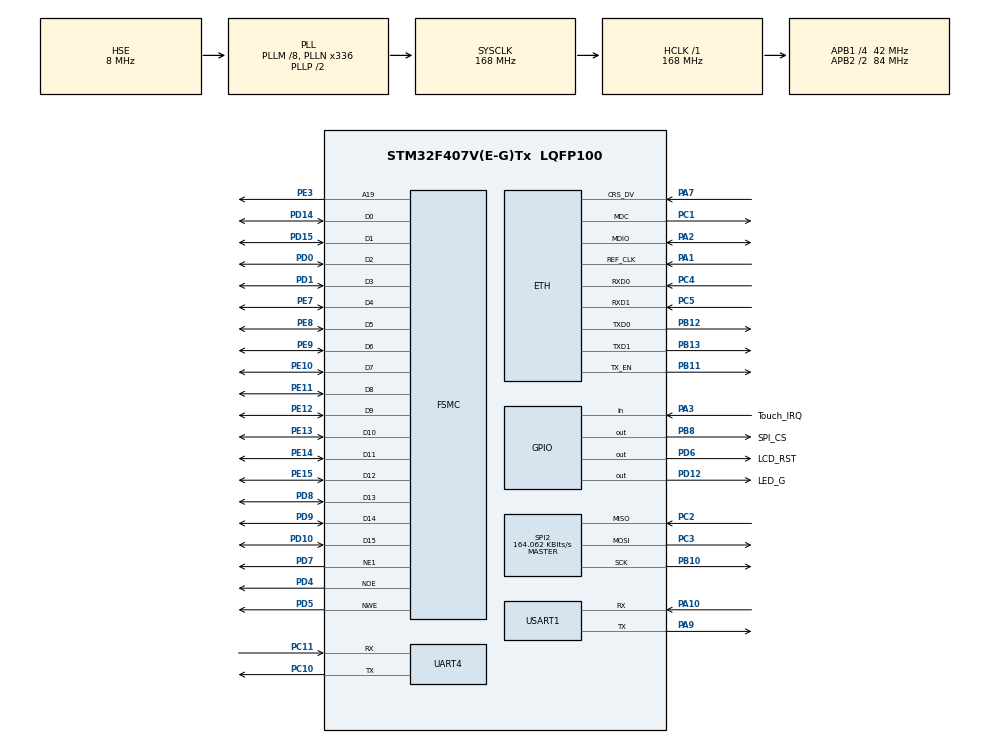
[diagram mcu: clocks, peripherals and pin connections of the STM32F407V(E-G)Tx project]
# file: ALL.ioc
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ETH.MediaInterface=ETH_MEDIA_INTERFACE_RMII
LWIP.GATEWAY_ADDRESS=192.168.000.102
LWIP.IP_ADDRESS=192.168.000.103
LWIP.LWIP_DHCP=0
LWIP.NETMASK_ADDRESS=255.255.255.000
LWIP.Version=v1.5.0_RC0_20160211_Cube
Mcu.Family=STM32F4
Mcu.Name=STM32F407V(E-G)Tx
Mcu.Package=LQFP100
NVIC.PriorityGroup=NVIC_PRIORITYGROUP_4
PA1.Mode=RMII
PA1.Signal=ETH_REF_CLK
PA10.Mode=Asynchronous
PA10.Signal=USART1_RX
PA13.Mode=JTAG_5_pins
PA13.Signal=SYS_JTMS-SWDIO
PA14.Mode=JTAG_5_pins
PA14.Signal=SYS_JTCK-SWCLK
PA15.Mode=JTAG_5_pins
PA15.Signal=SYS_JTDI
PA2.Mode=RMII
PA2.Signal=ETH_MDIO
PA3.GPIO_Label=Touch_IRQ
PA3.Signal=GPIO_Input
PA7.Mode=RMII
PA7.Signal=ETH_CRS_DV
PA9.Mode=Asynchronous
PA9.Signal=USART1_TX
PB10.Mode=Full_Duplex_Master
PB10.Signal=SPI2_SCK
PB11.Mode=RMII
PB11.Signal=ETH_TX_EN
PB12.Mode=RMII
PB12.Signal=ETH_TXD0
PB13.Mode=RMII
PB13.Signal=ETH_TXD1
PB3.Mode=JTAG_5_pins
PB3.Signal=SYS_JTDO-SWO
PB4.Mode=JTAG_5_pins
PB4.Signal=SYS_JTRST
PB8.GPIO_Label=SPI_CS
PB8.Signal=GPIO_Output
PC1.Mode=RMII
PC1.Signal=ETH_MDC
PC10.Mode=Asynchronous
PC10.Signal=UART4_TX
PC11.Mode=Asynchronous
PC11.Signal=UART4_RX
PC2.Mode=Full_Duplex_Master
PC2.Signal=SPI2_MISO
PC3.Mode=Full_Duplex_Master
PC3.Signal=SPI2_MOSI
PC4.Mode=RMII
PC4.Signal=ETH_RXD0
PC5.Mode=RMII
PC5.Signal=ETH_RXD1
PD0.Mode=16b-d1
PD0.Signal=FSMC_D2
PD1.Mode=16b-d1
PD1.Signal=FSMC_D3
PD10.Mode=16b-d1
PD10.Signal=FSMC_D15
PD12.GPIO_Label=LED_G
PD12.Signal=GPIO_Output
PD14.Mode=16b-d1
PD14.Signal=FSMC_D0
PD15.Mode=16b-d1
PD15.Signal=FSMC_D1
PD4.Mode=Lcd1
PD4.Signal=FSMC_NOE
PD5.Mode=Lcd1
PD5.Signal=FSMC_NWE
PD6.GPIO_Label=LCD_RST
PD6.Signal=GPIO_Output
PD7.Mode=NorPsramChipSelect1_1
PD7.Signal=FSMC_NE1
PD8.Mode=16b-d1
PD8.Signal=FSMC_D13
PD9.Mode=16b-d1
PD9.Signal=FSMC_D14
PE10.Mode=16b-d1
PE10.Signal=FSMC_D7
PE11.Mode=16b-d1
PE11.Signal=FSMC_D8
PE12.Mode=16b-d1
PE12.Signal=FSMC_D9
PE13.Mode=16b-d1
PE13.Signal=FSMC_D10
PE14.Mode=16b-d1
PE14.Signal=FSMC_D11
PE15.Mode=16b-d1
PE15.Signal=FSMC_D12
PE3.Mode=A19_1
PE3.Signal=FSMC_A19
PE7.Mode=16b-d1
PE7.Signal=FSMC_D4
PE8.Mode=16b-d1
PE8.Signal=FSMC_D5
PE9.Mode=16b-d1
PE9.Signal=FSMC_D6
PH0-OSC_IN.Mode=HSE-External-Oscillator
PH0-OSC_IN.Signal=RCC_OSC_IN
PH1-OSC_OUT.Mode=HSE-External-Oscillator
PH1-OSC_OUT.Signal=RCC_OSC_OUT
RCC.48MHZClocksFreq_Value=84000000
RCC.AHBFreq_Value=168000000
RCC.APB1CLKDivider=RCC_HCLK_DIV4
RCC.APB1Freq_Value=42000000
RCC.APB1TimFreq_Value=84000000
RCC.APB2CLKDivider=RCC_HCLK_DIV2
RCC.APB2Freq_Value=84000000
RCC.APB2TimFreq_Value=168000000
RCC.CortexFreq_Value=168000000
RCC.HCLKFreq_Value=168000000
RCC.HSE_VALUE=8000000
RCC.HSI_VALUE=16000000
RCC.LSE_VALUE=32768
RCC.PLLM=8
RCC.PLLN=336
RCC.PLLSourceVirtual=RCC_PLLSOURCE_HSE
RCC.SYSCLKFreq_VALUE=168000000
RCC.SYSCLKSource=RCC_SYSCLKSOURCE_PLLCLK
RCC.VCOOutputFreq_Value=336000000
SPI2.BaudRatePrescaler=SPI_BAUDRATEPRESCALER_256
SPI2.CalculateBaudRate=164.062 KBits/s
SPI2.Mode=SPI_MODE_MASTER
VP_LWIP_VS_Enabled.Mode=Enabled

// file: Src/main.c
/**
  ******************************************************************************
  * File Name          : main.c
  * Description        : Main program body
  ******************************************************************************
  *Example of working LwIP Stack and EmWin GUI interface
  *By Lopashchenko Ivan 28.02.2017 A.D
  *****************************************************************************/
#include "main.h"       //some Pin definition
#include "stm32f4xx_hal.h"
#include "lwip.h"       //TCP-IP STACK

/* USER CODE BEGIN Includes */
#include "lwip.h"          //TCP-IP STACK
#include "LCD_ini.h"      //LCD INIT
#include "XPT2046.h"     //Touchscreen
#include "GUI.h"        //GUI
#include "WindowDLG.h" //определения функций
#include "my_tcp.h"    //фунция определения пересыла TCP
#include "WIDGET_Multipage.h"
/* USER CODE END Includes */

SPI_HandleTypeDef hspi2;

UART_HandleTypeDef huart4;
UART_HandleTypeDef huart1;

SRAM_HandleTypeDef hsram1;

/* USER CODE BEGIN PV */
//extern int touch_y, touch_x;    //global var. for touch
//extern unsigned char touch_en; //touch Interrupt(1-pressed)
extern GUI_CONST_STORAGE GUI_FONT GUI_FontArial16;
/* Private variables ---------------------------------------------------------*/

/* USER CODE END PV */

void SystemClock_Config(void);
void Error_Handler(void);
static void MX_GPIO_Init(void);
static void MX_FSMC_Init(void);
static void MX_SPI2_Init(void);
static void MX_UART4_Init(void);
static void MX_USART1_UART_Init(void);

/* USER CODE BEGIN PFP */
/* Private function prototypes -----------------------------------------------*/
extern struct netif gnetif;
char transmitBuffer[256];
char receiveBuffer[512];
char rec[512];
//uint8_t IP_ADDRESS[4];
/* USER CODE END PFP */

/* USER CODE BEGIN 0 */
void User_notification(struct netif *netif)
{
  if (netif_is_up(&gnetif))
  {
    GUI_SetFont(&GUI_FontArial16);
    GUI_SetBkColor(GUI_DARKGREEN);
    GUI_Clear();
    GUI_SetTextMode(GUI_TM_NORMAL);
    GUI_DispStringHCenterAt("LWIP Инициализирован" , 160, 10);
    GUI_DispStringHCenterAt("Версия гр.библиотеки:", 160, 30);
    GUI_DispStringHCenterAt((GUI_GetVersionString()), 160, 50);
    //GUI_DispStringHCenterAt(("IP_IS_%i",(const char *)IP_ADDRESS) , 260, 10);
    //GUI_DispString("netif_is_up");
    /* Turn On LED 1 to indicate ETH and LwIP init success*/
    //HAL_GPIO_WritePin(GPIOD, GPIO_PIN_15, GPIO_PIN_SET);
  }
  else
  {
    GUI_SetFont(&GUI_Font8x16);
    GUI_SetBkColor(GUI_BLUE);
    GUI_Clear();
    GUI_SetTextMode(GUI_TM_NORMAL);
    GUI_DispStringHCenterAt("LWIP_IS_NOT_INIT_PROPERLY" , 160, 10);
    /* Turn On LED 2 to indicate ETH and LwIP init error */
    //HAL_GPIO_WritePin(GPIOD, GPIO_PIN_13, GPIO_PIN_SET);
  }
}
/* USER CODE END 0 */

int main(void)
{

  /* USER CODE BEGIN 1 */
  extern char rec[512];
  /* USER CODE END 1 */

  /* MCU Configuration----------------------------------------------------------*/

  /* Reset of all peripherals, Initializes the Flash interface and the Systick. */
  HAL_Init();

  /* Configure the system clock */
  SystemClock_Config();

  /* Initialize all configured peripherals */
  MX_GPIO_Init();
  MX_FSMC_Init();
  MX_SPI2_Init();
  MX_UART4_Init();
  MX_USART1_UART_Init();
  MX_LWIP_Init();
  /* USER CODE BEGIN 2 */
   //LCD_ini();
  //LCD_Clear(0x051F);
  __HAL_RCC_CRC_CLK_ENABLE();   //for GUI INIT only
  GUI_Init();                   //GUI INIT
  //CreateWindow();
  XPT2046_Init();
  MyTCP_init();
  //Createtest();
  //User_notification(&gnetif);
  MainTask();
  /* USER CODE END 2 */

  /* Infinite loop */
  /* USER CODE BEGIN WHILE */
  while (1)
  {
  //MX_LWIP_Process();
//    GUI_Delay(100);
//    //GUI_DispStringHCenterAt(rec, 160, 40);
  /* USER CODE END WHILE */
  }

}

/** System Clock Configuration
*/
void SystemClock_Config(void)
{

  RCC_OscInitTypeDef RCC_OscInitStruct;
  RCC_ClkInitTypeDef RCC_ClkInitStruct;

    /**Configure the main internal regulator output voltage
    */
  __HAL_RCC_PWR_CLK_ENABLE();

  __HAL_PWR_VOLTAGESCALING_CONFIG(PWR_REGULATOR_VOLTAGE_SCALE1);

    /**Initializes the CPU, AHB and APB busses clocks
    */
  RCC_OscInitStruct.OscillatorType = RCC_OSCILLATORTYPE_HSE;
  RCC_OscInitStruct.HSEState = RCC_HSE_ON;
  RCC_OscInitStruct.PLL.PLLState = RCC_PLL_ON;
  RCC_OscInitStruct.PLL.PLLSource = RCC_PLLSOURCE_HSE;
  RCC_OscInitStruct.PLL.PLLM = 8;
  RCC_OscInitStruct.PLL.PLLN = 336;
  RCC_OscInitStruct.PLL.PLLP = RCC_PLLP_DIV2;
  RCC_OscInitStruct.PLL.PLLQ = 4;
  if (HAL_RCC_OscConfig(&RCC_OscInitStruct) != HAL_OK)
  {
    Error_Handler();
  }

    /**Initializes the CPU, AHB and APB busses clocks
    */
  RCC_ClkInitStruct.ClockType = RCC_CLOCKTYPE_HCLK|RCC_CLOCKTYPE_SYSCLK
                              |RCC_CLOCKTYPE_PCLK1|RCC_CLOCKTYPE_PCLK2;
  RCC_ClkInitStruct.SYSCLKSource = RCC_SYSCLKSOURCE_PLLCLK;
  RCC_ClkInitStruct.AHBCLKDivider = RCC_SYSCLK_DIV1;
  RCC_ClkInitStruct.APB1CLKDivider = RCC_HCLK_DIV4;
  RCC_ClkInitStruct.APB2CLKDivider = RCC_HCLK_DIV2;

  if (HAL_RCC_ClockConfig(&RCC_ClkInitStruct, FLASH_LATENCY_5) != HAL_OK)
  {
    Error_Handler();
  }

    /**Configure the Systick interrupt time
    */
  HAL_SYSTICK_Config(HAL_RCC_GetHCLKFreq()/1000);

    /**Configure the Systick
    */
  HAL_SYSTICK_CLKSourceConfig(SYSTICK_CLKSOURCE_HCLK);

  /* SysTick_IRQn interrupt configuration */
  HAL_NVIC_SetPriority(SysTick_IRQn, 0, 0);
}

/* SPI2 init function */
static void MX_SPI2_Init(void)
{

  hspi2.Instance = SPI2;
  hspi2.Init.Mode = SPI_MODE_MASTER;
  hspi2.Init.Direction = SPI_DIRECTION_2LINES;
  hspi2.Init.DataSize = SPI_DATASIZE_8BIT;
  hspi2.Init.CLKPolarity = SPI_POLARITY_LOW;
  hspi2.Init.CLKPhase = SPI_PHASE_1EDGE;
  hspi2.Init.NSS = SPI_NSS_SOFT;
  hspi2.Init.BaudRatePrescaler = SPI_BAUDRATEPRESCALER_256;
  hspi2.Init.FirstBit = SPI_FIRSTBIT_MSB;
  hspi2.Init.TIMode = SPI_TIMODE_DISABLE;
  hspi2.Init.CRCCalculation = SPI_CRCCALCULATION_DISABLE;
  hspi2.Init.CRCPolynomial = 10;
  if (HAL_SPI_Init(&hspi2) != HAL_OK)
  {
    Error_Handler();
  }

}

/* UART4 init function */
static void MX_UART4_Init(void)
{

  huart4.Instance = UART4;
  huart4.Init.BaudRate = 115200;
  huart4.Init.WordLength = UART_WORDLENGTH_8B;
  huart4.Init.StopBits = UART_STOPBITS_1;
  huart4.Init.Parity = UART_PARITY_NONE;
  huart4.Init.Mode = UART_MODE_TX_RX;
  huart4.Init.HwFlowCtl = UART_HWCONTROL_NONE;
  huart4.Init.OverSampling = UART_OVERSAMPLING_16;
  if (HAL_UART_Init(&huart4) != HAL_OK)
  {
    Error_Handler();
  }

}

/* USART1 init function */
static void MX_USART1_UART_Init(void)
{

  huart1.Instance = USART1;
  huart1.Init.BaudRate = 115200;
  huart1.Init.WordLength = UART_WORDLENGTH_8B;
  huart1.Init.StopBits = UART_STOPBITS_1;
  huart1.Init.Parity = UART_PARITY_NONE;
  huart1.Init.Mode = UART_MODE_TX_RX;
  huart1.Init.HwFlowCtl = UART_HWCONTROL_NONE;
  huart1.Init.OverSampling = UART_OVERSAMPLING_16;
  if (HAL_UART_Init(&huart1) != HAL_OK)
  {
    Error_Handler();
  }

}

/** Configure pins as
        * Analog
        * Input
        * Output
        * EVENT_OUT
        * EXTI
*/
static void MX_GPIO_Init(void)
{

  GPIO_InitTypeDef GPIO_InitStruct;

  /* GPIO Ports Clock Enable */
  __HAL_RCC_GPIOE_CLK_ENABLE();
  __HAL_RCC_GPIOH_CLK_ENABLE();
  __HAL_RCC_GPIOC_CLK_ENABLE();
  __HAL_RCC_GPIOA_CLK_ENABLE();
  __HAL_RCC_GPIOB_CLK_ENABLE();
  __HAL_RCC_GPIOD_CLK_ENABLE();

  /*Configure GPIO pin Output Level */
  HAL_GPIO_WritePin(GPIOD, LED_G_Pin|LCD_CS_Pin, GPIO_PIN_RESET);
  HAL_GPIO_WritePin(GPIOD, GPIO_PIN_13, GPIO_PIN_RESET);

  /*Configure GPIO pin Output Level */
  HAL_GPIO_WritePin(SPI_CS_GPIO_Port, SPI_CS_Pin, GPIO_PIN_RESET);

  /*Configure GPIO pin : Touch_IRQ_Pin */
  GPIO_InitStruct.Pin = Touch_IRQ_Pin;
  GPIO_InitStruct.Mode = GPIO_MODE_INPUT;
  GPIO_InitStruct.Pull = GPIO_NOPULL;
  HAL_GPIO_Init(Touch_IRQ_GPIO_Port, &GPIO_InitStruct);

  /*Configure GPIO pins : LED_G_Pin LCD_CS_Pin */
  GPIO_InitStruct.Pin = GPIO_PIN_13|LED_G_Pin|LCD_CS_Pin;
  GPIO_InitStruct.Mode = GPIO_MODE_OUTPUT_PP;
  GPIO_InitStruct.Pull = GPIO_NOPULL;
  GPIO_InitStruct.Speed = GPIO_SPEED_FREQ_LOW;
  HAL_GPIO_Init(GPIOD, &GPIO_InitStruct);

  /*Configure GPIO pin : SPI_CS_Pin */
  GPIO_InitStruct.Pin = SPI_CS_Pin;
  GPIO_InitStruct.Mode = GPIO_MODE_OUTPUT_PP;
  GPIO_InitStruct.Pull = GPIO_NOPULL;
  GPIO_InitStruct.Speed = GPIO_SPEED_FREQ_LOW;
  HAL_GPIO_Init(SPI_CS_GPIO_Port, &GPIO_InitStruct);

}

/* FSMC initialization function */
static void MX_FSMC_Init(void)
{
  FSMC_NORSRAM_TimingTypeDef Timing;

  /** Perform the SRAM1 memory initialization sequence
  */
  hsram1.Instance = FSMC_NORSRAM_DEVICE;
  hsram1.Extended = FSMC_NORSRAM_EXTENDED_DEVICE;
  /* hsram1.Init */
  hsram1.Init.NSBank = FSMC_NORSRAM_BANK1;
  hsram1.Init.DataAddressMux = FSMC_DATA_ADDRESS_MUX_DISABLE;
  hsram1.Init.MemoryType = FSMC_MEMORY_TYPE_SRAM;
  hsram1.Init.MemoryDataWidth = FSMC_NORSRAM_MEM_BUS_WIDTH_16;
  hsram1.Init.BurstAccessMode = FSMC_BURST_ACCESS_MODE_DISABLE;
  hsram1.Init.WaitSignalPolarity = FSMC_WAIT_SIGNAL_POLARITY_LOW;
  hsram1.Init.WrapMode = FSMC_WRAP_MODE_DISABLE;
  hsram1.Init.WaitSignalActive = FSMC_WAIT_TIMING_BEFORE_WS;
  hsram1.Init.WriteOperation = FSMC_WRITE_OPERATION_ENABLE;
  hsram1.Init.WaitSignal = FSMC_WAIT_SIGNAL_DISABLE;
  hsram1.Init.ExtendedMode = FSMC_EXTENDED_MODE_DISABLE;
  hsram1.Init.AsynchronousWait = FSMC_ASYNCHRONOUS_WAIT_DISABLE;
  hsram1.Init.WriteBurst = FSMC_WRITE_BURST_DISABLE;
  hsram1.Init.PageSize = FSMC_PAGE_SIZE_NONE;
  /* Timing */
  Timing.AddressSetupTime = 15;
  Timing.AddressHoldTime = 15;
  Timing.DataSetupTime = 255;
  Timing.BusTurnAroundDuration = 15;
  Timing.CLKDivision = 16;
  Timing.DataLatency = 17;
  Timing.AccessMode = FSMC_ACCESS_MODE_A;
  /* ExtTiming */

  if (HAL_SRAM_Init(&hsram1, &Timing, NULL) != HAL_OK)
  {
    Error_Handler();
  }

}

void Error_Handler(void)
{
  while(1)
  {
  }
}

/************************ (C) COPYRIGHT STMicroelectronics *****END OF FILE****/
